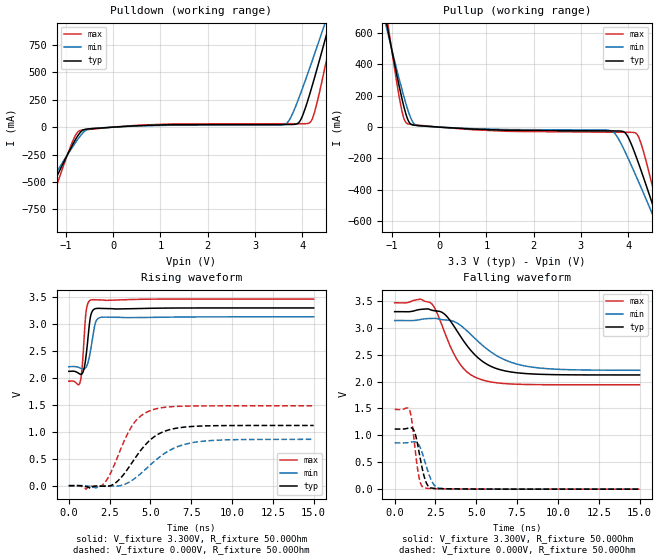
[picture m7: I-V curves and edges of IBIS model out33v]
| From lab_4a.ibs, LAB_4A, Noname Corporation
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[Model]   out33v
Model_type   Output
Vmeas = 1.400V
Vref = 1.400V
Cref = 5.000pF
Rref = 100.000Ohm
|   typ   min   max
C_comp   4.550pF   2.600pF   6.500pF
[Voltage Range]   3.300V   3.135V   3.465V
[Temperature Range]   50.0   100.0   0.0
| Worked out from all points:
|   slope of the pulldown table from 0 to 0.495 V, typ, clamps not added: 40.2 ohm
|   slope of the pullup table from 0 to 0.495 V, typ, clamps not added: 56.8 ohm
|   falling waveform, V_fixture 3.300V, R_fixture 50.00Ohm: 20-80 % time 1.91ns typ, 2.42ns min, 1.46ns max; typ from 3.3 V to 2.12 V
|   rising waveform, V_fixture 3.300V, R_fixture 50.00Ohm: 20-80 % time 254ps typ, 314ps min, 203ps max; typ from 2.12 V to 3.3 V
|   rising waveform, V_fixture 0.000V, R_fixture 50.00Ohm: 20-80 % time 1.77ns typ, 2.19ns min, 1.4ns max; typ from 0 V to 1.12 V
|   falling waveform, V_fixture 0.000V, R_fixture 50.00Ohm: 20-80 % time 455ps typ, 565ps min, 358ps max; typ from 1.12 V to 0 V
[Pulldown]
|   Voltage   I(typ)   I(min)   I(max)
-3.3V     -2.416A    -1.934A    -3.285A
-1.82V    -1.025A    -854mA     -1.334A
-1.495V   -723.9mA   -620.3mA   -911.6mA
-895mV    -188.7mA   -202.4mA   -167.5mA
-695mV    -46.69mA   -79.19mA   -29.44mA
3.635V    24.02mA    25.87mA    31.15mA
3.945V    51.97mA    284.2mA    31.27mA
4.15V     289.8mA    530.3mA    37.95mA
4.42V     698.1mA    869.7mA    425.4mA
4.525V    863.5mA    1.004A     636.9mA
4.68V     1.111A     1.203A     960.2mA
6.6V      4.259A     3.723A     5.152A
[Pullup]
|   Voltage   I(typ)   I(min)   I(max)
-3.3V     4.234A     3.486A     5.484A
-1.21V    816.3mA    756mA      919.3mA
-1.06V    581.6mA    567.8mA    607.3mA
-790mV    185.9mA    244mA      106.6mA
-655mV    42.99mA    103.1mA    20.44mA
-420mV    9.277mA    7.886mA    12.15mA
3.64V     -24.11mA   -22.59mA   -32.3mA
3.925V    -33.37mA   -151.4mA   -32.75mA
4.155V    -177.6mA   -304.2mA   -37.27mA
4.31V     -309.4mA   -411.9mA   -141.5mA
4.725V    -684.1mA   -707.3mA   -642.8mA
6.6V      -2.444A    -2.077A    -3.103A
[Ramp]
R_load = 50.00Ohm
|   typ   min   max
dV/dt_r   670.917mV/1.770ns   516.401mV/2.186ns   889.721mV/1.396ns
dV/dt_f   706.191mV/1.908ns   555.207mV/2.414ns   914.908mV/1.460ns
[Falling Waveform]
V_fixture = 3.300V
V_fixture_min = 3.135V
V_fixture_max = 3.465V
R_fixture = 50.00Ohm
|   Time   V(typ)   V(min)   V(max)
0s        3.3V       3.135V     3.465V
1.6ns     3.342V     3.156V     3.534V
2.25ns    3.329V     3.173V     3.451V
3ns       3.267V     3.148V     2.962V
3.9ns     2.903V     3.074V     2.371V
4.5ns     2.641V     2.923V     2.163V
5.275ns   2.4V       2.701V     2.04V
6.525ns   2.215V     2.436V     1.968V
8.1ns     2.148V     2.284V     1.946V
15ns      2.123V     2.21V      1.94V
[Rising Waveform]
V_fixture = 3.300V
V_fixture_min = 3.135V
V_fixture_max = 3.465V
R_fixture = 50.00Ohm
|   Time   V(typ)   V(min)   V(max)
0s        2.123V     2.21V      1.94V
700ps     2.071V     2.184V     1.929V
825ps     2.084V     2.169V     2.218V
950ps     2.194V     2.169V     2.791V
1.05ns    2.386V     2.196V     3.206V
1.175ns   2.738V     2.288V     3.389V
1.35ns    3.164V     2.536V     3.447V
1.65ns    3.288V     3.038V     3.451V
2ns       3.291V     3.127V     3.448V
15ns      3.3V       3.135V     3.465V
[Rising Waveform]
V_fixture = 0.000V
V_fixture_min = 0.000V
V_fixture_max = 0.000V
R_fixture = 50.00Ohm
|   Time   V(typ)   V(min)   V(max)
0s        210.1nV    237.2nV    148.9nV
1.05ns    -15.52mV   -3.878mV   -64.53mV
2.1ns     -10.15mV   -4.258mV   22.66mV
2.95ns    73.49mV    -6.577mV   505.4mV
3.9ns     439.4mV    103.9mV    1.122V
4.425ns   663.1mV    229.1mV    1.297V
5.125ns   883.8mV    422.3mV    1.408V
6.325ns   1.051V     679.1mV    1.468V
7.675ns   1.102V     804.9mV    1.48V
15ns      1.118V     860.7mV    1.483V
[Falling Waveform]
V_fixture = 0.000V
V_fixture_min = 0.000V
V_fixture_max = 0.000V
R_fixture = 50.00Ohm
|   Time   V(typ)   V(min)   V(max)
0s        1.118V     860.7mV    1.483V
925ps     1.143V     869.6mV    1.458V
1.05ns    1.137V     876.7mV    1.274V
1.225ns   1.058V     880.5mV    815.9mV
1.475ns   719.9mV    826.5mV    245.5mV
1.625ns   478.9mV    727.9mV    79.69mV
1.825ns   215.6mV    538.8mV    27.5mV
2.275ns   20.83mV    147.3mV    11.92mV
2.7ns     8.028mV    18.61mV    6.792mV
15ns      210.1nV    237.2nV    148.9nV
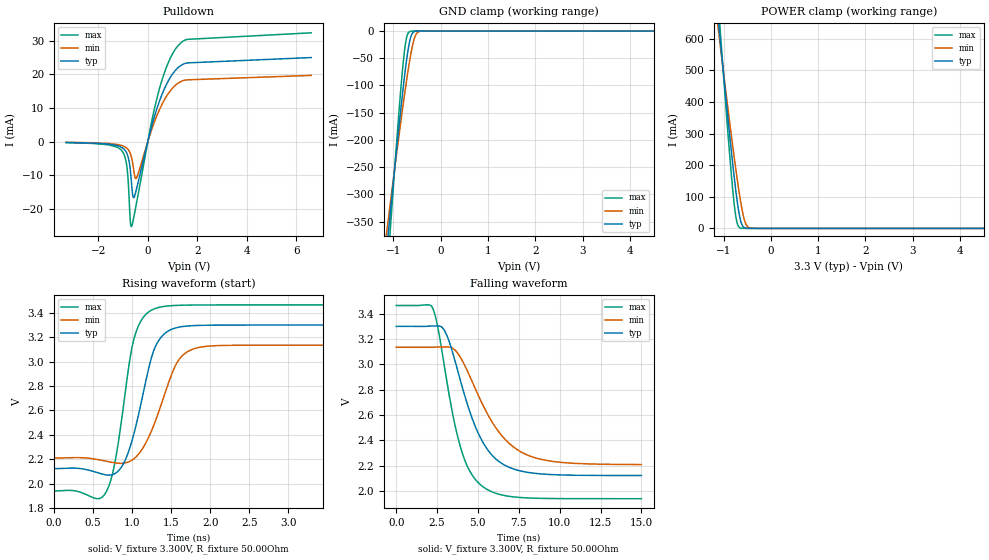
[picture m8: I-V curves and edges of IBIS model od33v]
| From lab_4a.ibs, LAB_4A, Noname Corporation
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[Model]   od33v
Model_type   I/O_open_sink
Vinl = 800.000mV
Vinh = 2.000V
Vmeas = 1.400V
Vref = 1.400V
Cref = 5.000pF
Rref = 100.000Ohm
|   typ   min   max
C_comp   4.550pF   2.600pF   6.500pF
[Voltage Range]   3.300V   3.135V   3.465V
[Temperature Range]   50.0   100.0   0.0
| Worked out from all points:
|   slope of the pulldown table from 0 to 0.495 V, typ, clamps not added: 39.6 ohm
|   GND clamp passes 1 mA (typ) near -0.56 V on its own axis
|   POWER clamp passes 1 mA (typ) near -0.54 V on its own axis
|   falling waveform, V_fixture 3.300V, R_fixture 50.00Ohm: 20-80 % time 1.91ns typ, 2.42ns min, 1.46ns max; typ from 3.3 V to 2.12 V
|   rising waveform, V_fixture 3.300V, R_fixture 50.00Ohm: 20-80 % time 261ps typ, 319ps min, 213ps max; typ from 2.12 V to 3.3 V
[Pulldown]
|   Voltage   I(typ)   I(min)   I(max)
-3.3V     -256.4uA   -208.9uA   -311.8uA
-1.04V    -1.786mA   -1.195mA   -2.784mA
-840mV    -3.589mA   -2.018mA   -7.696mA
-785mV    -4.824mA   -2.467mA   -12.52mA
-710mV    -8.173mA   -3.47mA    -23.22mA
-665mV    -11.73mA   -4.471mA   -25.24mA
-590mV    -16.53mA   -7.344mA   -23.33mA
-465mV    -14.31mA   -10.91mA   -18.6mA
415mV     10.84mA    8.569mA    14.2mA
845mV     18.27mA    14.46mA    23.76mA
1.22V     21.96mA    17.35mA    28.49mA
6.6V      24.96mA    19.66mA    32.31mA
[GND Clamp]
|   Voltage   I(typ)   I(min)   I(max)
-3.3V     -2.416A    -1.934A    -3.285A
-1.14V    -399.6mA   -368.2mA   -457.3mA
-1.095V   -359.4mA   -336.9mA   -401.3mA
-1.065V   -332.8mA   -316.1mA   -364.2mA
-900mV    -190.1mA   -204mA     -167.9mA
-795mV    -105.4mA   -135.7mA   -59.93mA
-730mV    -58.86mA   -95.74mA   -15.61mA
-650mV    -16.44mA   -51.23mA   -860.1uA
-605mV    -5.03mA    -30.33mA   -124.6uA
-545mV    -680.9uA   -10.68mA   -9.758uA
-415mV    -6.553uA   -288.9uA   -39.92nA
6.6V      0A         0A         0A
[POWER Clamp]
|   Voltage   I(typ)   I(min)   I(max)
-3.3V     4.234A     3.486A     5.484A
-1.115V   666mA      635.7mA    719.1mA
-1.09V    627mA      604.4mA    667.2mA
-1.05V    564.9mA    554.6mA    585mA
-875mV    301.5mA    341.4mA    241.3mA
-780mV    169.5mA    231.1mA    84.52mA
-715mV    90.19mA    159.9mA    18.73mA
-650mV    31.09mA    95.27mA    1.638mA
-600mV    8.404mA    53.33mA    201.2uA
-545mV    1.357mA    20.63mA    19.51uA
-415mV    13.11uA    576.9uA    78.41nA
6.6V      0A         0A         0A
[Ramp]
R_load = 50.00Ohm
|   typ   min   max
dV/dt_r   706.191mV/261.272ps 555.207mV/319.123ps 914.909mV/213.470ps
dV/dt_f   706.191mV/1.911ns   555.207mV/2.417ns   914.909mV/1.464ns
[Falling Waveform]
V_fixture = 3.300V
V_fixture_min = 3.135V
V_fixture_max = 3.465V
R_fixture = 50.00Ohm
|   Time   V(typ)   V(min)   V(max)
0s        3.3V       3.135V     3.465V
2.225ns   3.303V     3.135V     3.446V
2.525ns   3.303V     3.137V     3.306V
2.975ns   3.262V     3.137V     2.964V
3.875ns   2.898V     3.067V     2.374V
4.475ns   2.637V     2.914V     2.164V
5.25ns    2.398V     2.693V     2.04V
6.5ns     2.215V     2.432V     1.969V
8.1ns     2.147V     2.281V     1.946V
15ns      2.123V     2.21V      1.94V
[Rising Waveform]
V_fixture = 3.300V
V_fixture_min = 3.135V
V_fixture_max = 3.465V
R_fixture = 50.00Ohm
|   Time   V(typ)   V(min)   V(max)
0s        2.123V     2.21V      1.94V
675ps     2.07V      2.183V     1.937V
775ps     2.08V      2.171V     2.151V
875ps     2.145V     2.166V     2.56V
1.05ns    2.472V     2.217V     3.239V
1.25ns    3.035V     2.433V     3.422V
1.4ns     3.22V      2.698V     3.452V
1.625ns   3.286V     3.036V     3.462V
2.05ns    3.299V     3.13V      3.465V
15ns      3.3V       3.135V     3.465V
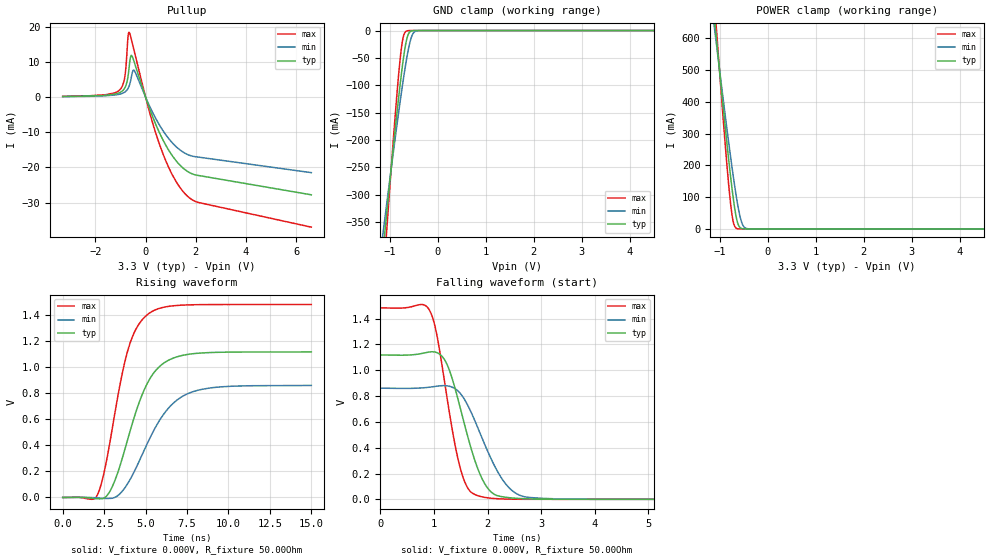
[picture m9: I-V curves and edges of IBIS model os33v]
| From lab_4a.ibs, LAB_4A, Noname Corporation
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[Model]   os33v
Model_type   I/O_open_source
Vinl = 800.000mV
Vinh = 2.000V
Vmeas = 1.400V
Vref = 1.400V
Cref = 5.000pF
Rref = 100.000Ohm
|   typ   min   max
C_comp   4.550pF   2.600pF   6.500pF
[Voltage Range]   3.300V   3.135V   3.465V
[Temperature Range]   50.0   100.0   0.0
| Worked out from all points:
|   slope of the pullup table from 0 to 0.495 V, typ, clamps not added: 53.7 ohm
|   GND clamp passes 1 mA (typ) near -0.56 V on its own axis
|   POWER clamp passes 1 mA (typ) near -0.54 V on its own axis
|   rising waveform, V_fixture 0.000V, R_fixture 50.00Ohm: 20-80 % time 1.77ns typ, 2.19ns min, 1.4ns max; typ from 0 V to 1.12 V
|   falling waveform, V_fixture 0.000V, R_fixture 50.00Ohm: 20-80 % time 461ps typ, 571ps min, 366ps max; typ from 1.12 V to 0 V
[GND Clamp]
|   Voltage   I(typ)   I(min)   I(max)
-3.3V     -2.416A    -1.934A    -3.285A
-1.14V    -399.6mA   -368.2mA   -457.3mA
-1.095V   -359.4mA   -336.9mA   -401.3mA
-1.065V   -332.8mA   -316.1mA   -364.2mA
-900mV    -190.1mA   -204mA     -167.9mA
-795mV    -105.4mA   -135.7mA   -59.93mA
-730mV    -58.86mA   -95.74mA   -15.61mA
-650mV    -16.44mA   -51.23mA   -860.1uA
-605mV    -5.03mA    -30.33mA   -124.6uA
-545mV    -680.9uA   -10.68mA   -9.758uA
-415mV    -6.553uA   -288.9uA   -39.92nA
6.6V      0A         0A         0A
[Pullup]
|   Voltage   I(typ)   I(min)   I(max)
-3.3V     186.4uA    149.5uA    232uA
-1.03V    1.292mA    851.1uA    2.057mA
-830mV    2.586mA    1.434mA    5.645mA
-700mV    5.874mA    2.463mA    17.07mA
-660mV    8.116mA    3.078mA    18.43mA
-580mV    11.82mA    5.211mA    16.82mA
-440mV    9.708mA    7.47mA     12.73mA
520mV     -9.616mA   -7.536mA   -12.71mA
1.025V    -16.25mA   -12.68mA   -21.53mA
1.55V     -20.51mA   -15.87mA   -27.31mA
2.105V    -22.27mA   -17.05mA   -29.95mA
6.6V      -27.77mA   -21.47mA   -36.97mA
[POWER Clamp]
|   Voltage   I(typ)   I(min)   I(max)
-3.3V     4.234A     3.486A     5.484A
-1.115V   666mA      635.7mA    719.1mA
-1.09V    627mA      604.4mA    667.2mA
-1.05V    564.9mA    554.6mA    585mA
-875mV    301.5mA    341.4mA    241.3mA
-780mV    169.5mA    231.1mA    84.52mA
-715mV    90.19mA    159.9mA    18.73mA
-650mV    31.09mA    95.27mA    1.638mA
-600mV    8.404mA    53.33mA    201.2uA
-545mV    1.357mA    20.63mA    19.51uA
-415mV    13.11uA    576.9uA    78.41nA
6.6V      0A         0A         0A
[Ramp]
R_load = 50.00Ohm
|   typ   min   max
dV/dt_r   670.918mV/1.773ns   516.401mV/2.188ns   889.722mV/1.400ns
dV/dt_f   670.918mV/461.369ps 516.401mV/570.790ps 889.722mV/365.753ps
[Rising Waveform]
V_fixture = 0.000V
V_fixture_min = 0.000V
V_fixture_max = 0.000V
R_fixture = 50.00Ohm
|   Time   V(typ)   V(min)   V(max)
0s        -68.64nV   234.3nV    46.42nV
2.1ns     -9.982mV   -3.589mV   21.4mV
2.5ns     -4.15mV    -6.992mV   194.2mV
2.925ns   65.61mV    -6.867mV   480.7mV
3.925ns   447.6mV    107.7mV    1.129V
4.45ns    669.9mV    233.9mV    1.301V
5.15ns    887.7mV    426.9mV    1.409V
6.425ns   1.057V     692.4mV    1.469V
7.925ns   1.105V     815.5mV    1.481V
15ns      1.118V     860.7mV    1.483V
[Falling Waveform]
V_fixture = 0.000V
V_fixture_min = 0.000V
V_fixture_max = 0.000V
R_fixture = 50.00Ohm
|   Time   V(typ)   V(min)   V(max)
0s        1.118V     860.7mV    1.483V
925ps     1.142V     869.3mV    1.46V
1.05ns    1.138V     876.2mV    1.285V
1.225ns   1.062V     880.3mV    841mV
1.5ns     694.2mV    816.9mV    229.3mV
1.65ns    458.1mV    713.1mV    75.92mV
1.875ns   180.6mV    497.9mV    21.52mV
2.35ns    15.41mV    113.8mV    2.099mV
2.825ns   2.774mV    13.18mV    189.8uV
15ns      -68.64nV   234.3nV    46.42nV
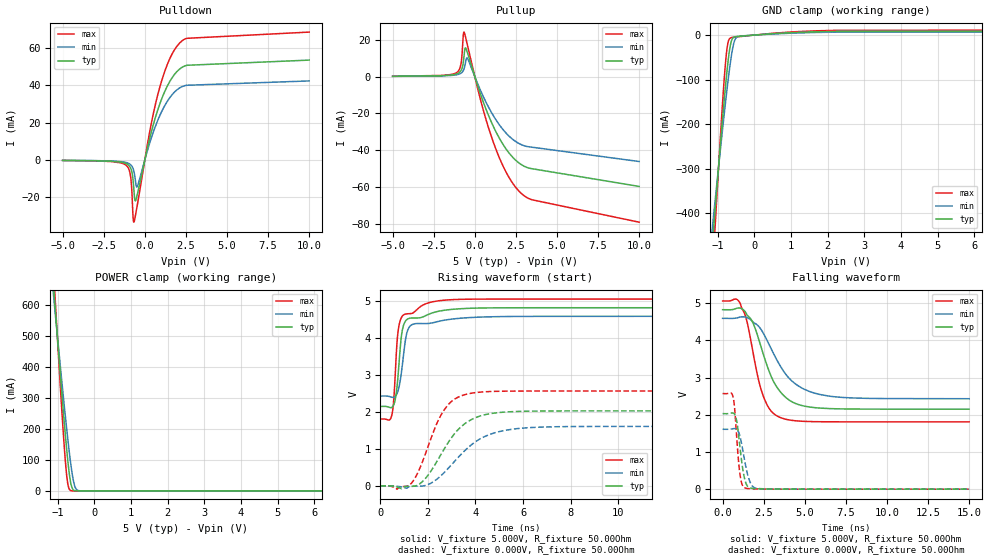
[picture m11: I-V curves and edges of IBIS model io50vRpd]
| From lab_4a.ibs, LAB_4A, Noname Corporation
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[Model]   io50vRpd
Model_type   I/O
Vinl = 800.000mV
Vinh = 2.000V
Vmeas = 1.400V
Vref = 1.400V
Cref = 5.000pF
Rref = 100.000Ohm
|   typ   min   max
C_comp   4.550pF   2.600pF   6.500pF
[Voltage Range]   5.000V   4.750V   5.250V
[Temperature Range]   50.0   100.0   0.0
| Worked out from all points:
|   slope of the pulldown table from 0 to 0.75 V, typ, clamps not added: 29.2 ohm
|   slope of the pullup table from 0 to 0.75 V, typ, clamps not added: 39 ohm
|   POWER clamp passes 1 mA (typ) near -0.53 V on its own axis
|   falling waveform, V_fixture 5.000V, R_fixture 50.00Ohm: 20-80 % time 1.39ns typ, 1.82ns min, 979ps max; typ from 4.82 V to 2.15 V
|   rising waveform, V_fixture 5.000V, R_fixture 50.00Ohm: 20-80 % time 248ps typ, 283ps min, 229ps max; typ from 2.15 V to 4.82 V
|   rising waveform, V_fixture 0.000V, R_fixture 50.00Ohm: 20-80 % time 1.3ns typ, 1.61ns min, 1ns max; typ from 0 V to 2.03 V
|   falling waveform, V_fixture 0.000V, R_fixture 50.00Ohm: 20-80 % time 351ps typ, 440ps min, 272ps max; typ from 2.03 V to 0 V
[Pulldown]
|   Voltage   I(typ)   I(min)   I(max)
-5V       -207.1uA   -171.2uA   -248.8uA
-1.13V    -1.927mA   -1.335mA   -2.852mA
-860mV    -4.389mA   -2.516mA   -9.027mA
-710mV    -11.07mA   -4.645mA   -31mA
-670mV    -15.23mA   -5.818mA   -33.25mA
-575mV    -21.91mA   -10.83mA   -29.94mA
-445mV    -18.01mA   -13.98mA   -23.51mA
265mV     10.33mA    8.149mA    13.57mA
790mV     26.82mA    21.25mA    34.93mA
1.37V     39.56mA    31.41mA    51.13mA
2.085V    48.39mA    38.37mA    62.25mA
10V       53.44mA    42.3mA     68.42mA
[GND Clamp]
|   Voltage   I(typ)   I(min)   I(max)
-5V       -4.698A    -3.716A    -6.466A
-1.135V   -461.3mA   -425.8mA   -526.7mA
-1.085V   -409.3mA   -385.2mA   -454.2mA
-1.06V    -383.5mA   -365.1mA   -418.3mA
-890mV    -212.6mA   -230.6mA   -184mA
-785mV    -115.3mA   -151.5mA   -62.82mA
-720mV    -62.85mA   -105.5mA   -18.48mA
-635mV    -16.66mA   -52.34mA   -5.963mA
-520mV    -3.79mA    -9.281mA   -4.547mA
-350mV    -2.38mA    -1.93mA    -3.112mA
2.255V    8.251mA    6.535mA    10.61mA
10V       8.596mA    6.776mA    11.05mA
[Pullup]
|   Voltage   I(typ)   I(min)   I(max)
-5V       149.8uA    122.3uA    183uA
-1.115V   1.394mA    953.8uA    2.1mA
-845mV    3.186mA    1.803mA    6.687mA
-660mV    10.77mA    4.082mA    24.18mA
-570mV    15.65mA    7.386mA    21.72mA
-440mV    12.84mA    9.88mA     16.84mA
340mV     -9.372mA   -7.373mA   -12.34mA
1.035V    -25.27mA   -19.83mA   -33.28mA
1.84V     -38.53mA   -30.1mA    -50.84mA
2.665V    -46.8mA    -36.26mA   -62.03mA
3.52V     -50.13mA   -38.44mA   -67.04mA
10V       -59.71mA   -46.16mA   -79.14mA
[POWER Clamp]
|   Voltage   I(typ)   I(min)   I(max)
-5V       7.053A     5.739A     9.248A
-1.11V    658.2mA    629.5mA    708.8mA
-1.08V    611.5mA    592mA      646.7mA
-1.055V   572.7mA    560.9mA    595.3mA
-885mV    316.1mA    353.3mA    259.8mA
-780mV    169.6mA    231.1mA    84.57mA
-715mV    90.24mA    160mA      18.78mA
-640mV    24.87mA    86.23mA    1.129mA
-575mV    3.818mA    36.39mA    112.5uA
-525mV    703.9uA    13.2mA     47.42uA
-340mV    21.96uA    74.36uA    25.32uA
10V       0A         0A         0A
[Ramp]
R_load = 50.00Ohm
|   typ   min   max
dV/dt_r   1.217V/1.302ns   965.699mV/1.613ns   1.541V/999.524ps
dV/dt_f   1.604V/1.386ns   1.296V/1.815ns   1.949V/979.064ps
[Falling Waveform]
V_fixture = 5.000V
V_fixture_min = 4.750V
V_fixture_max = 5.250V
R_fixture = 50.00Ohm
|   Time   V(typ)   V(min)   V(max)
0s        4.822V     4.59V      5.057V
1.05ns    4.866V     4.622V     5.008V
1.475ns   4.69V      4.611V     4.517V
1.8ns     4.509V     4.514V     3.795V
2.425ns   3.699V     4.23V      2.562V
2.85ns    3.145V     3.868V     2.156V
3.4ns     2.679V     3.393V     1.948V
4.4ns     2.308V     2.839V     1.839V
5.925ns   2.179V     2.544V     1.812V
15ns      2.15V      2.43V      1.809V
[Rising Waveform]
V_fixture = 5.000V
V_fixture_min = 4.750V
V_fixture_max = 5.250V
R_fixture = 50.00Ohm
|   Time   V(typ)   V(min)   V(max)
0s        2.15V      2.43V      1.809V
500ps     2.13V      2.397V     1.959V
575ps     2.208V     2.398V     2.402V
725ps     2.82V      2.535V     4.05V
850ps     3.819V     2.897V     4.499V
975ps     4.342V     3.531V     4.625V
1.175ns   4.524V     4.248V     4.66V
1.975ns   4.628V     4.394V     4.944V
4.15ns    4.814V     4.568V     5.055V
15ns      4.822V     4.59V      5.057V
[Rising Waveform]
V_fixture = 0.000V
V_fixture_min = 0.000V
V_fixture_max = 0.000V
R_fixture = 50.00Ohm
|   Time   V(typ)   V(min)   V(max)
0s        30.84nV    269.6nV    24.31nV
700ps     -30.23mV   -10.89mV   -90.22mV
1.3ns     -13.55mV   -12.15mV   65.19mV
1.85ns    165.5mV    2.888mV    784.5mV
2.6ns     903.4mV    304.8mV    1.968V
3.025ns   1.331V     593.8mV    2.302V
3.575ns   1.692V     967mV      2.472V
4.45ns    1.933V     1.353V     2.548V
5.75ns    2.014V     1.549V     2.566V
15ns      2.029V     1.609V     2.568V
[Falling Waveform]
V_fixture = 0.000V
V_fixture_min = 0.000V
V_fixture_max = 0.000V
R_fixture = 50.00Ohm
|   Time   V(typ)   V(min)   V(max)
0s        2.029V     1.609V     2.568V
650ps     2.044V     1.625V     2.453V
725ps     2.014V     1.628V     2.201V
850ps     1.846V     1.611V     1.439V
1.05ns    1.154V     1.433V     423mV
1.2ns     617.5mV    1.113V     108.4mV
1.375ns   220mV      688.3mV    32.99mV
1.7ns     28.95mV    161.9mV    11.27mV
2.1ns     10.73mV    22.1mV     6.425mV
15ns      30.84nV    269.6nV    24.31nV
